# Generated by FakeRAM 2.0
VERSION 5.7 ;
BUSBITCHARS "[]" ;
PROPERTYDEFINITIONS
  MACRO width INTEGER ;
  MACRO depth INTEGER ;
  MACRO banks INTEGER ;
END PROPERTYDEFINITIONS
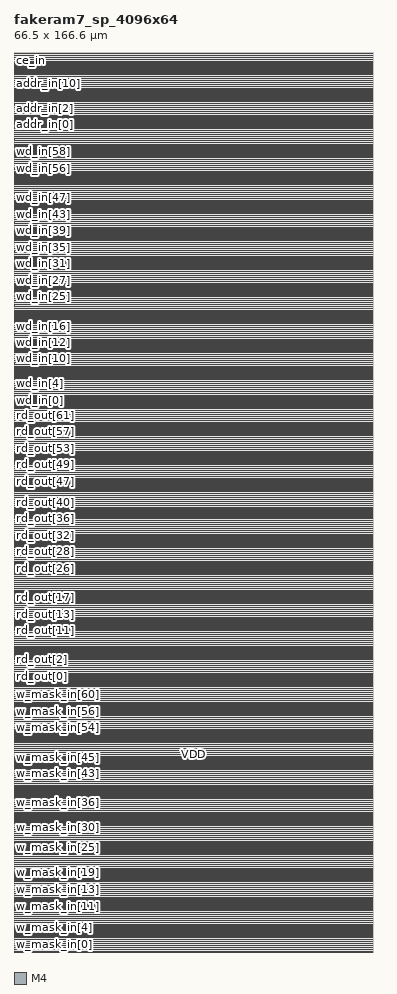
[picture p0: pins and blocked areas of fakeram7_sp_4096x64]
MACRO fakeram7_sp_4096x64
  PROPERTY width 64 ;
  PROPERTY depth 4096 ;
  PROPERTY banks 8 ;
  FOREIGN fakeram7_sp_4096x64 0 0 ;
  SYMMETRY X Y ;
  SIZE 66.500 BY 166.600 ;
  CLASS BLOCK ;
  PIN w_mask_in[0]
    DIRECTION INPUT ;
    USE SIGNAL ;
    SHAPE ABUTMENT ;
    PORT
      LAYER M4 ;
      RECT 0.000 0.048 0.024 0.072 ;
    END
  END w_mask_in[0]
  PIN w_mask_in[1]
    DIRECTION INPUT ;
    USE SIGNAL ;
    SHAPE ABUTMENT ;
    PORT
      LAYER M4 ;
      RECT 0.000 0.816 0.024 0.840 ;
    END
  END w_mask_in[1]
  PIN w_mask_in[2]
    DIRECTION INPUT ;
    USE SIGNAL ;
    SHAPE ABUTMENT ;
    PORT
      LAYER M4 ;
      RECT 0.000 1.584 0.024 1.608 ;
    END
  END w_mask_in[2]
  PIN w_mask_in[3]
    DIRECTION INPUT ;
    USE SIGNAL ;
    SHAPE ABUTMENT ;
    PORT
      LAYER M4 ;
      RECT 0.000 2.352 0.024 2.376 ;
    END
  END w_mask_in[3]
  PIN w_mask_in[4]
    DIRECTION INPUT ;
    USE SIGNAL ;
    SHAPE ABUTMENT ;
    PORT
      LAYER M4 ;
      RECT 0.000 3.120 0.024 3.144 ;
    END
  END w_mask_in[4]
  PIN w_mask_in[5]
    DIRECTION INPUT ;
    USE SIGNAL ;
    SHAPE ABUTMENT ;
    PORT
      LAYER M4 ;
      RECT 0.000 3.888 0.024 3.912 ;
    END
  END w_mask_in[5]
  PIN w_mask_in[6]
    DIRECTION INPUT ;
    USE SIGNAL ;
    SHAPE ABUTMENT ;
    PORT
      LAYER M4 ;
      RECT 0.000 4.656 0.024 4.680 ;
    END
  END w_mask_in[6]
  PIN w_mask_in[7]
    DIRECTION INPUT ;
    USE SIGNAL ;
    SHAPE ABUTMENT ;
    PORT
      LAYER M4 ;
      RECT 0.000 5.424 0.024 5.448 ;
    END
  END w_mask_in[7]
  PIN w_mask_in[8]
    DIRECTION INPUT ;
    USE SIGNAL ;
    SHAPE ABUTMENT ;
    PORT
      LAYER M4 ;
      RECT 0.000 6.192 0.024 6.216 ;
    END
  END w_mask_in[8]
  PIN w_mask_in[9]
    DIRECTION INPUT ;
    USE SIGNAL ;
    SHAPE ABUTMENT ;
    PORT
      LAYER M4 ;
      RECT 0.000 6.960 0.024 6.984 ;
    END
  END w_mask_in[9]
  PIN w_mask_in[10]
    DIRECTION INPUT ;
    USE SIGNAL ;
    SHAPE ABUTMENT ;
    PORT
      LAYER M4 ;
      RECT 0.000 7.728 0.024 7.752 ;
    END
  END w_mask_in[10]
  PIN w_mask_in[11]
    DIRECTION INPUT ;
    USE SIGNAL ;
    SHAPE ABUTMENT ;
    PORT
      LAYER M4 ;
      RECT 0.000 8.496 0.024 8.520 ;
    END
  END w_mask_in[11]
  PIN w_mask_in[12]
    DIRECTION INPUT ;
    USE SIGNAL ;
    SHAPE ABUTMENT ;
    PORT
      LAYER M4 ;
      RECT 0.000 9.264 0.024 9.288 ;
    END
  END w_mask_in[12]
  PIN w_mask_in[13]
    DIRECTION INPUT ;
    USE SIGNAL ;
    SHAPE ABUTMENT ;
    PORT
      LAYER M4 ;
      RECT 0.000 10.032 0.024 10.056 ;
    END
  END w_mask_in[13]
  PIN w_mask_in[14]
    DIRECTION INPUT ;
    USE SIGNAL ;
    SHAPE ABUTMENT ;
    PORT
      LAYER M4 ;
      RECT 0.000 10.800 0.024 10.824 ;
    END
  END w_mask_in[14]
  PIN w_mask_in[15]
    DIRECTION INPUT ;
    USE SIGNAL ;
    SHAPE ABUTMENT ;
    PORT
      LAYER M4 ;
      RECT 0.000 11.568 0.024 11.592 ;
    END
  END w_mask_in[15]
  PIN w_mask_in[16]
    DIRECTION INPUT ;
    USE SIGNAL ;
    SHAPE ABUTMENT ;
    PORT
      LAYER M4 ;
      RECT 0.000 12.336 0.024 12.360 ;
    END
  END w_mask_in[16]
  PIN w_mask_in[17]
    DIRECTION INPUT ;
    USE SIGNAL ;
    SHAPE ABUTMENT ;
    PORT
      LAYER M4 ;
      RECT 0.000 13.104 0.024 13.128 ;
    END
  END w_mask_in[17]
  PIN w_mask_in[18]
    DIRECTION INPUT ;
    USE SIGNAL ;
    SHAPE ABUTMENT ;
    PORT
      LAYER M4 ;
      RECT 0.000 13.872 0.024 13.896 ;
    END
  END w_mask_in[18]
  PIN w_mask_in[19]
    DIRECTION INPUT ;
    USE SIGNAL ;
    SHAPE ABUTMENT ;
    PORT
      LAYER M4 ;
      RECT 0.000 14.640 0.024 14.664 ;
    END
  END w_mask_in[19]
  PIN w_mask_in[20]
    DIRECTION INPUT ;
    USE SIGNAL ;
    SHAPE ABUTMENT ;
    PORT
      LAYER M4 ;
      RECT 0.000 15.408 0.024 15.432 ;
    END
  END w_mask_in[20]
  PIN w_mask_in[21]
    DIRECTION INPUT ;
    USE SIGNAL ;
    SHAPE ABUTMENT ;
    PORT
      LAYER M4 ;
      RECT 0.000 16.176 0.024 16.200 ;
    END
  END w_mask_in[21]
  PIN w_mask_in[22]
    DIRECTION INPUT ;
    USE SIGNAL ;
    SHAPE ABUTMENT ;
    PORT
      LAYER M4 ;
      RECT 0.000 16.944 0.024 16.968 ;
    END
  END w_mask_in[22]
  PIN w_mask_in[23]
    DIRECTION INPUT ;
    USE SIGNAL ;
    SHAPE ABUTMENT ;
    PORT
      LAYER M4 ;
      RECT 0.000 17.712 0.024 17.736 ;
    END
  END w_mask_in[23]
  PIN w_mask_in[24]
    DIRECTION INPUT ;
    USE SIGNAL ;
    SHAPE ABUTMENT ;
    PORT
      LAYER M4 ;
      RECT 0.000 18.480 0.024 18.504 ;
    END
  END w_mask_in[24]
  PIN w_mask_in[25]
    DIRECTION INPUT ;
    USE SIGNAL ;
    SHAPE ABUTMENT ;
    PORT
      LAYER M4 ;
      RECT 0.000 19.248 0.024 19.272 ;
    END
  END w_mask_in[25]
  PIN w_mask_in[26]
    DIRECTION INPUT ;
    USE SIGNAL ;
    SHAPE ABUTMENT ;
    PORT
      LAYER M4 ;
      RECT 0.000 20.016 0.024 20.040 ;
    END
  END w_mask_in[26]
  PIN w_mask_in[27]
    DIRECTION INPUT ;
    USE SIGNAL ;
    SHAPE ABUTMENT ;
    PORT
      LAYER M4 ;
      RECT 0.000 20.784 0.024 20.808 ;
    END
  END w_mask_in[27]
  PIN w_mask_in[28]
    DIRECTION INPUT ;
    USE SIGNAL ;
    SHAPE ABUTMENT ;
    PORT
      LAYER M4 ;
      RECT 0.000 21.552 0.024 21.576 ;
    END
  END w_mask_in[28]
  PIN w_mask_in[29]
    DIRECTION INPUT ;
    USE SIGNAL ;
    SHAPE ABUTMENT ;
    PORT
      LAYER M4 ;
      RECT 0.000 22.320 0.024 22.344 ;
    END
  END w_mask_in[29]
  PIN w_mask_in[30]
    DIRECTION INPUT ;
    USE SIGNAL ;
    SHAPE ABUTMENT ;
    PORT
      LAYER M4 ;
      RECT 0.000 23.088 0.024 23.112 ;
    END
  END w_mask_in[30]
  PIN w_mask_in[31]
    DIRECTION INPUT ;
    USE SIGNAL ;
    SHAPE ABUTMENT ;
    PORT
      LAYER M4 ;
      RECT 0.000 23.856 0.024 23.880 ;
    END
  END w_mask_in[31]
  PIN w_mask_in[32]
    DIRECTION INPUT ;
    USE SIGNAL ;
    SHAPE ABUTMENT ;
    PORT
      LAYER M4 ;
      RECT 0.000 24.624 0.024 24.648 ;
    END
  END w_mask_in[32]
  PIN w_mask_in[33]
    DIRECTION INPUT ;
    USE SIGNAL ;
    SHAPE ABUTMENT ;
    PORT
      LAYER M4 ;
      RECT 0.000 25.392 0.024 25.416 ;
    END
  END w_mask_in[33]
  PIN w_mask_in[34]
    DIRECTION INPUT ;
    USE SIGNAL ;
    SHAPE ABUTMENT ;
    PORT
      LAYER M4 ;
      RECT 0.000 26.160 0.024 26.184 ;
    END
  END w_mask_in[34]
  PIN w_mask_in[35]
    DIRECTION INPUT ;
    USE SIGNAL ;
    SHAPE ABUTMENT ;
    PORT
      LAYER M4 ;
      RECT 0.000 26.928 0.024 26.952 ;
    END
  END w_mask_in[35]
  PIN w_mask_in[36]
    DIRECTION INPUT ;
    USE SIGNAL ;
    SHAPE ABUTMENT ;
    PORT
      LAYER M4 ;
      RECT 0.000 27.696 0.024 27.720 ;
    END
  END w_mask_in[36]
  PIN w_mask_in[37]
    DIRECTION INPUT ;
    USE SIGNAL ;
    SHAPE ABUTMENT ;
    PORT
      LAYER M4 ;
      RECT 0.000 28.464 0.024 28.488 ;
    END
  END w_mask_in[37]
  PIN w_mask_in[38]
    DIRECTION INPUT ;
    USE SIGNAL ;
    SHAPE ABUTMENT ;
    PORT
      LAYER M4 ;
      RECT 0.000 29.232 0.024 29.256 ;
    END
  END w_mask_in[38]
  PIN w_mask_in[39]
    DIRECTION INPUT ;
    USE SIGNAL ;
    SHAPE ABUTMENT ;
    PORT
      LAYER M4 ;
      RECT 0.000 30.000 0.024 30.024 ;
    END
  END w_mask_in[39]
  PIN w_mask_in[40]
    DIRECTION INPUT ;
    USE SIGNAL ;
    SHAPE ABUTMENT ;
    PORT
      LAYER M4 ;
      RECT 0.000 30.768 0.024 30.792 ;
    END
  END w_mask_in[40]
  PIN w_mask_in[41]
    DIRECTION INPUT ;
    USE SIGNAL ;
    SHAPE ABUTMENT ;
    PORT
      LAYER M4 ;
      RECT 0.000 31.536 0.024 31.560 ;
    END
  END w_mask_in[41]
  PIN w_mask_in[42]
    DIRECTION INPUT ;
    USE SIGNAL ;
    SHAPE ABUTMENT ;
    PORT
      LAYER M4 ;
      RECT 0.000 32.304 0.024 32.328 ;
    END
  END w_mask_in[42]
  PIN w_mask_in[43]
    DIRECTION INPUT ;
    USE SIGNAL ;
    SHAPE ABUTMENT ;
    PORT
      LAYER M4 ;
      RECT 0.000 33.072 0.024 33.096 ;
    END
  END w_mask_in[43]
  PIN w_mask_in[44]
    DIRECTION INPUT ;
    USE SIGNAL ;
    SHAPE ABUTMENT ;
    PORT
      LAYER M4 ;
      RECT 0.000 33.840 0.024 33.864 ;
    END
  END w_mask_in[44]
  PIN w_mask_in[45]
    DIRECTION INPUT ;
    USE SIGNAL ;
    SHAPE ABUTMENT ;
    PORT
      LAYER M4 ;
      RECT 0.000 34.608 0.024 34.632 ;
    END
  END w_mask_in[45]
  PIN w_mask_in[46]
    DIRECTION INPUT ;
    USE SIGNAL ;
    SHAPE ABUTMENT ;
    PORT
      LAYER M4 ;
      RECT 0.000 35.376 0.024 35.400 ;
    END
  END w_mask_in[46]
  PIN w_mask_in[47]
    DIRECTION INPUT ;
    USE SIGNAL ;
    SHAPE ABUTMENT ;
    PORT
      LAYER M4 ;
      RECT 0.000 36.144 0.024 36.168 ;
    END
  END w_mask_in[47]
  PIN w_mask_in[48]
    DIRECTION INPUT ;
    USE SIGNAL ;
    SHAPE ABUTMENT ;
    PORT
      LAYER M4 ;
      RECT 0.000 36.912 0.024 36.936 ;
    END
  END w_mask_in[48]
  PIN w_mask_in[49]
    DIRECTION INPUT ;
    USE SIGNAL ;
    SHAPE ABUTMENT ;
    PORT
      LAYER M4 ;
      RECT 0.000 37.680 0.024 37.704 ;
    END
  END w_mask_in[49]
  PIN w_mask_in[50]
    DIRECTION INPUT ;
    USE SIGNAL ;
    SHAPE ABUTMENT ;
    PORT
      LAYER M4 ;
      RECT 0.000 38.448 0.024 38.472 ;
    END
  END w_mask_in[50]
  PIN w_mask_in[51]
    DIRECTION INPUT ;
    USE SIGNAL ;
    SHAPE ABUTMENT ;
    PORT
      LAYER M4 ;
      RECT 0.000 39.216 0.024 39.240 ;
    END
  END w_mask_in[51]
  PIN w_mask_in[52]
    DIRECTION INPUT ;
    USE SIGNAL ;
    SHAPE ABUTMENT ;
    PORT
      LAYER M4 ;
      RECT 0.000 39.984 0.024 40.008 ;
    END
  END w_mask_in[52]
  PIN w_mask_in[53]
    DIRECTION INPUT ;
    USE SIGNAL ;
    SHAPE ABUTMENT ;
    PORT
      LAYER M4 ;
      RECT 0.000 40.752 0.024 40.776 ;
    END
  END w_mask_in[53]
  PIN w_mask_in[54]
    DIRECTION INPUT ;
    USE SIGNAL ;
    SHAPE ABUTMENT ;
    PORT
      LAYER M4 ;
      RECT 0.000 41.520 0.024 41.544 ;
    END
  END w_mask_in[54]
  PIN w_mask_in[55]
    DIRECTION INPUT ;
    USE SIGNAL ;
    SHAPE ABUTMENT ;
    PORT
      LAYER M4 ;
      RECT 0.000 42.288 0.024 42.312 ;
    END
  END w_mask_in[55]
  PIN w_mask_in[56]
    DIRECTION INPUT ;
    USE SIGNAL ;
    SHAPE ABUTMENT ;
    PORT
      LAYER M4 ;
      RECT 0.000 43.056 0.024 43.080 ;
    END
  END w_mask_in[56]
  PIN w_mask_in[57]
    DIRECTION INPUT ;
    USE SIGNAL ;
    SHAPE ABUTMENT ;
    PORT
      LAYER M4 ;
      RECT 0.000 43.824 0.024 43.848 ;
    END
  END w_mask_in[57]
  PIN w_mask_in[58]
    DIRECTION INPUT ;
    USE SIGNAL ;
    SHAPE ABUTMENT ;
    PORT
      LAYER M4 ;
      RECT 0.000 44.592 0.024 44.616 ;
    END
  END w_mask_in[58]
  PIN w_mask_in[59]
    DIRECTION INPUT ;
    USE SIGNAL ;
    SHAPE ABUTMENT ;
    PORT
      LAYER M4 ;
      RECT 0.000 45.360 0.024 45.384 ;
    END
  END w_mask_in[59]
  PIN w_mask_in[60]
    DIRECTION INPUT ;
    USE SIGNAL ;
    SHAPE ABUTMENT ;
    PORT
      LAYER M4 ;
      RECT 0.000 46.128 0.024 46.152 ;
    END
  END w_mask_in[60]
  PIN w_mask_in[61]
    DIRECTION INPUT ;
    USE SIGNAL ;
    SHAPE ABUTMENT ;
    PORT
      LAYER M4 ;
      RECT 0.000 46.896 0.024 46.920 ;
    END
  END w_mask_in[61]
  PIN w_mask_in[62]
    DIRECTION INPUT ;
    USE SIGNAL ;
    SHAPE ABUTMENT ;
    PORT
      LAYER M4 ;
      RECT 0.000 47.664 0.024 47.688 ;
    END
  END w_mask_in[62]
  PIN w_mask_in[63]
    DIRECTION INPUT ;
    USE SIGNAL ;
    SHAPE ABUTMENT ;
    PORT
      LAYER M4 ;
      RECT 0.000 48.432 0.024 48.456 ;
    END
  END w_mask_in[63]
  PIN rd_out[0]
    DIRECTION OUTPUT ;
    USE SIGNAL ;
    SHAPE ABUTMENT ;
    PORT
      LAYER M4 ;
      RECT 0.000 51.072 0.024 51.096 ;
    END
  END rd_out[0]
  PIN rd_out[1]
    DIRECTION OUTPUT ;
    USE SIGNAL ;
    SHAPE ABUTMENT ;
    PORT
      LAYER M4 ;
      RECT 0.000 51.840 0.024 51.864 ;
    END
  END rd_out[1]
  PIN rd_out[2]
    DIRECTION OUTPUT ;
    USE SIGNAL ;
    SHAPE ABUTMENT ;
    PORT
      LAYER M4 ;
      RECT 0.000 52.608 0.024 52.632 ;
    END
  END rd_out[2]
  PIN rd_out[3]
    DIRECTION OUTPUT ;
    USE SIGNAL ;
    SHAPE ABUTMENT ;
    PORT
      LAYER M4 ;
      RECT 0.000 53.376 0.024 53.400 ;
    END
  END rd_out[3]
  PIN rd_out[4]
    DIRECTION OUTPUT ;
    USE SIGNAL ;
    SHAPE ABUTMENT ;
    PORT
      LAYER M4 ;
      RECT 0.000 54.144 0.024 54.168 ;
    END
  END rd_out[4]
  PIN rd_out[5]
    DIRECTION OUTPUT ;
    USE SIGNAL ;
    SHAPE ABUTMENT ;
    PORT
      LAYER M4 ;
      RECT 0.000 54.912 0.024 54.936 ;
    END
  END rd_out[5]
  PIN rd_out[6]
    DIRECTION OUTPUT ;
    USE SIGNAL ;
    SHAPE ABUTMENT ;
    PORT
      LAYER M4 ;
      RECT 0.000 55.680 0.024 55.704 ;
    END
  END rd_out[6]
  PIN rd_out[7]
    DIRECTION OUTPUT ;
    USE SIGNAL ;
    SHAPE ABUTMENT ;
    PORT
      LAYER M4 ;
      RECT 0.000 56.448 0.024 56.472 ;
    END
  END rd_out[7]
  PIN rd_out[8]
    DIRECTION OUTPUT ;
    USE SIGNAL ;
    SHAPE ABUTMENT ;
    PORT
      LAYER M4 ;
      RECT 0.000 57.216 0.024 57.240 ;
    END
  END rd_out[8]
  PIN rd_out[9]
    DIRECTION OUTPUT ;
    USE SIGNAL ;
    SHAPE ABUTMENT ;
    PORT
      LAYER M4 ;
      RECT 0.000 57.984 0.024 58.008 ;
    END
  END rd_out[9]
  PIN rd_out[10]
    DIRECTION OUTPUT ;
    USE SIGNAL ;
    SHAPE ABUTMENT ;
    PORT
      LAYER M4 ;
      RECT 0.000 58.752 0.024 58.776 ;
    END
  END rd_out[10]
  PIN rd_out[11]
    DIRECTION OUTPUT ;
    USE SIGNAL ;
    SHAPE ABUTMENT ;
    PORT
      LAYER M4 ;
      RECT 0.000 59.520 0.024 59.544 ;
    END
  END rd_out[11]
  PIN rd_out[12]
    DIRECTION OUTPUT ;
    USE SIGNAL ;
    SHAPE ABUTMENT ;
    PORT
      LAYER M4 ;
      RECT 0.000 60.288 0.024 60.312 ;
    END
  END rd_out[12]
  PIN rd_out[13]
    DIRECTION OUTPUT ;
    USE SIGNAL ;
    SHAPE ABUTMENT ;
    PORT
      LAYER M4 ;
      RECT 0.000 61.056 0.024 61.080 ;
    END
  END rd_out[13]
  PIN rd_out[14]
    DIRECTION OUTPUT ;
    USE SIGNAL ;
    SHAPE ABUTMENT ;
    PORT
      LAYER M4 ;
      RECT 0.000 61.824 0.024 61.848 ;
    END
  END rd_out[14]
  PIN rd_out[15]
    DIRECTION OUTPUT ;
    USE SIGNAL ;
    SHAPE ABUTMENT ;
    PORT
      LAYER M4 ;
      RECT 0.000 62.592 0.024 62.616 ;
    END
  END rd_out[15]
  PIN rd_out[16]
    DIRECTION OUTPUT ;
    USE SIGNAL ;
    SHAPE ABUTMENT ;
    PORT
      LAYER M4 ;
      RECT 0.000 63.360 0.024 63.384 ;
    END
  END rd_out[16]
  PIN rd_out[17]
    DIRECTION OUTPUT ;
    USE SIGNAL ;
    SHAPE ABUTMENT ;
    PORT
      LAYER M4 ;
      RECT 0.000 64.128 0.024 64.152 ;
    END
  END rd_out[17]
  PIN rd_out[18]
    DIRECTION OUTPUT ;
    USE SIGNAL ;
    SHAPE ABUTMENT ;
    PORT
      LAYER M4 ;
      RECT 0.000 64.896 0.024 64.920 ;
    END
  END rd_out[18]
  PIN rd_out[19]
    DIRECTION OUTPUT ;
    USE SIGNAL ;
    SHAPE ABUTMENT ;
    PORT
      LAYER M4 ;
      RECT 0.000 65.664 0.024 65.688 ;
    END
  END rd_out[19]
  PIN rd_out[20]
    DIRECTION OUTPUT ;
    USE SIGNAL ;
    SHAPE ABUTMENT ;
    PORT
      LAYER M4 ;
      RECT 0.000 66.432 0.024 66.456 ;
    END
  END rd_out[20]
  PIN rd_out[21]
    DIRECTION OUTPUT ;
    USE SIGNAL ;
    SHAPE ABUTMENT ;
    PORT
      LAYER M4 ;
      RECT 0.000 67.200 0.024 67.224 ;
    END
  END rd_out[21]
  PIN rd_out[22]
    DIRECTION OUTPUT ;
    USE SIGNAL ;
    SHAPE ABUTMENT ;
    PORT
      LAYER M4 ;
      RECT 0.000 67.968 0.024 67.992 ;
    END
  END rd_out[22]
  PIN rd_out[23]
    DIRECTION OUTPUT ;
    USE SIGNAL ;
    SHAPE ABUTMENT ;
    PORT
      LAYER M4 ;
      RECT 0.000 68.736 0.024 68.760 ;
    END
  END rd_out[23]
  PIN rd_out[24]
    DIRECTION OUTPUT ;
    USE SIGNAL ;
    SHAPE ABUTMENT ;
    PORT
      LAYER M4 ;
      RECT 0.000 69.504 0.024 69.528 ;
    END
  END rd_out[24]
  PIN rd_out[25]
    DIRECTION OUTPUT ;
    USE SIGNAL ;
    SHAPE ABUTMENT ;
    PORT
      LAYER M4 ;
      RECT 0.000 70.272 0.024 70.296 ;
    END
  END rd_out[25]
  PIN rd_out[26]
    DIRECTION OUTPUT ;
    USE SIGNAL ;
    SHAPE ABUTMENT ;
    PORT
      LAYER M4 ;
      RECT 0.000 71.040 0.024 71.064 ;
    END
  END rd_out[26]
  PIN rd_out[27]
    DIRECTION OUTPUT ;
    USE SIGNAL ;
    SHAPE ABUTMENT ;
    PORT
      LAYER M4 ;
      RECT 0.000 71.808 0.024 71.832 ;
    END
  END rd_out[27]
  PIN rd_out[28]
    DIRECTION OUTPUT ;
    USE SIGNAL ;
    SHAPE ABUTMENT ;
    PORT
      LAYER M4 ;
      RECT 0.000 72.576 0.024 72.600 ;
    END
  END rd_out[28]
  PIN rd_out[29]
    DIRECTION OUTPUT ;
    USE SIGNAL ;
    SHAPE ABUTMENT ;
    PORT
      LAYER M4 ;
      RECT 0.000 73.344 0.024 73.368 ;
    END
  END rd_out[29]
  PIN rd_out[30]
    DIRECTION OUTPUT ;
    USE SIGNAL ;
    SHAPE ABUTMENT ;
    PORT
      LAYER M4 ;
      RECT 0.000 74.112 0.024 74.136 ;
    END
  END rd_out[30]
  PIN rd_out[31]
    DIRECTION OUTPUT ;
    USE SIGNAL ;
    SHAPE ABUTMENT ;
    PORT
      LAYER M4 ;
      RECT 0.000 74.880 0.024 74.904 ;
    END
  END rd_out[31]
  PIN rd_out[32]
    DIRECTION OUTPUT ;
    USE SIGNAL ;
    SHAPE ABUTMENT ;
    PORT
      LAYER M4 ;
      RECT 0.000 75.648 0.024 75.672 ;
    END
  END rd_out[32]
  PIN rd_out[33]
    DIRECTION OUTPUT ;
    USE SIGNAL ;
    SHAPE ABUTMENT ;
    PORT
      LAYER M4 ;
      RECT 0.000 76.416 0.024 76.440 ;
    END
  END rd_out[33]
  PIN rd_out[34]
    DIRECTION OUTPUT ;
    USE SIGNAL ;
    SHAPE ABUTMENT ;
    PORT
      LAYER M4 ;
      RECT 0.000 77.184 0.024 77.208 ;
    END
  END rd_out[34]
  PIN rd_out[35]
    DIRECTION OUTPUT ;
    USE SIGNAL ;
    SHAPE ABUTMENT ;
    PORT
      LAYER M4 ;
      RECT 0.000 77.952 0.024 77.976 ;
    END
  END rd_out[35]
  PIN rd_out[36]
    DIRECTION OUTPUT ;
    USE SIGNAL ;
    SHAPE ABUTMENT ;
    PORT
      LAYER M4 ;
      RECT 0.000 78.720 0.024 78.744 ;
    END
  END rd_out[36]
  PIN rd_out[37]
    DIRECTION OUTPUT ;
    USE SIGNAL ;
    SHAPE ABUTMENT ;
    PORT
      LAYER M4 ;
      RECT 0.000 79.488 0.024 79.512 ;
    END
  END rd_out[37]
  PIN rd_out[38]
    DIRECTION OUTPUT ;
    USE SIGNAL ;
    SHAPE ABUTMENT ;
    PORT
      LAYER M4 ;
      RECT 0.000 80.256 0.024 80.280 ;
    END
  END rd_out[38]
  PIN rd_out[39]
    DIRECTION OUTPUT ;
    USE SIGNAL ;
    SHAPE ABUTMENT ;
    PORT
      LAYER M4 ;
      RECT 0.000 81.024 0.024 81.048 ;
    END
  END rd_out[39]
  PIN rd_out[40]
    DIRECTION OUTPUT ;
    USE SIGNAL ;
    SHAPE ABUTMENT ;
    PORT
      LAYER M4 ;
      RECT 0.000 81.792 0.024 81.816 ;
    END
  END rd_out[40]
  PIN rd_out[41]
    DIRECTION OUTPUT ;
    USE SIGNAL ;
    SHAPE ABUTMENT ;
    PORT
      LAYER M4 ;
      RECT 0.000 82.560 0.024 82.584 ;
    END
  END rd_out[41]
  PIN rd_out[42]
    DIRECTION OUTPUT ;
    USE SIGNAL ;
    SHAPE ABUTMENT ;
    PORT
      LAYER M4 ;
      RECT 0.000 83.328 0.024 83.352 ;
    END
  END rd_out[42]
  PIN rd_out[43]
    DIRECTION OUTPUT ;
    USE SIGNAL ;
    SHAPE ABUTMENT ;
    PORT
      LAYER M4 ;
      RECT 0.000 84.096 0.024 84.120 ;
    END
  END rd_out[43]
  PIN rd_out[44]
    DIRECTION OUTPUT ;
    USE SIGNAL ;
    SHAPE ABUTMENT ;
    PORT
      LAYER M4 ;
      RECT 0.000 84.864 0.024 84.888 ;
    END
  END rd_out[44]
  PIN rd_out[45]
    DIRECTION OUTPUT ;
    USE SIGNAL ;
    SHAPE ABUTMENT ;
    PORT
      LAYER M4 ;
      RECT 0.000 85.632 0.024 85.656 ;
    END
  END rd_out[45]
  PIN rd_out[46]
    DIRECTION OUTPUT ;
    USE SIGNAL ;
    SHAPE ABUTMENT ;
    PORT
      LAYER M4 ;
      RECT 0.000 86.400 0.024 86.424 ;
    END
  END rd_out[46]
  PIN rd_out[47]
    DIRECTION OUTPUT ;
    USE SIGNAL ;
    SHAPE ABUTMENT ;
    PORT
      LAYER M4 ;
      RECT 0.000 87.168 0.024 87.192 ;
    END
  END rd_out[47]
  PIN rd_out[48]
    DIRECTION OUTPUT ;
    USE SIGNAL ;
    SHAPE ABUTMENT ;
    PORT
      LAYER M4 ;
      RECT 0.000 87.936 0.024 87.960 ;
    END
  END rd_out[48]
  PIN rd_out[49]
    DIRECTION OUTPUT ;
    USE SIGNAL ;
    SHAPE ABUTMENT ;
    PORT
      LAYER M4 ;
      RECT 0.000 88.704 0.024 88.728 ;
    END
  END rd_out[49]
  PIN rd_out[50]
    DIRECTION OUTPUT ;
    USE SIGNAL ;
    SHAPE ABUTMENT ;
    PORT
      LAYER M4 ;
      RECT 0.000 89.472 0.024 89.496 ;
    END
  END rd_out[50]
  PIN rd_out[51]
    DIRECTION OUTPUT ;
    USE SIGNAL ;
    SHAPE ABUTMENT ;
    PORT
      LAYER M4 ;
      RECT 0.000 90.240 0.024 90.264 ;
    END
  END rd_out[51]
  PIN rd_out[52]
    DIRECTION OUTPUT ;
    USE SIGNAL ;
    SHAPE ABUTMENT ;
    PORT
      LAYER M4 ;
      RECT 0.000 91.008 0.024 91.032 ;
    END
  END rd_out[52]
  PIN rd_out[53]
    DIRECTION OUTPUT ;
    USE SIGNAL ;
    SHAPE ABUTMENT ;
    PORT
      LAYER M4 ;
      RECT 0.000 91.776 0.024 91.800 ;
    END
  END rd_out[53]
  PIN rd_out[54]
    DIRECTION OUTPUT ;
    USE SIGNAL ;
    SHAPE ABUTMENT ;
    PORT
      LAYER M4 ;
      RECT 0.000 92.544 0.024 92.568 ;
    END
  END rd_out[54]
  PIN rd_out[55]
    DIRECTION OUTPUT ;
    USE SIGNAL ;
    SHAPE ABUTMENT ;
    PORT
      LAYER M4 ;
      RECT 0.000 93.312 0.024 93.336 ;
    END
  END rd_out[55]
  PIN rd_out[56]
    DIRECTION OUTPUT ;
    USE SIGNAL ;
    SHAPE ABUTMENT ;
    PORT
      LAYER M4 ;
      RECT 0.000 94.080 0.024 94.104 ;
    END
  END rd_out[56]
  PIN rd_out[57]
    DIRECTION OUTPUT ;
    USE SIGNAL ;
    SHAPE ABUTMENT ;
    PORT
      LAYER M4 ;
      RECT 0.000 94.848 0.024 94.872 ;
    END
  END rd_out[57]
  PIN rd_out[58]
    DIRECTION OUTPUT ;
    USE SIGNAL ;
    SHAPE ABUTMENT ;
    PORT
      LAYER M4 ;
      RECT 0.000 95.616 0.024 95.640 ;
    END
  END rd_out[58]
  PIN rd_out[59]
    DIRECTION OUTPUT ;
    USE SIGNAL ;
    SHAPE ABUTMENT ;
    PORT
      LAYER M4 ;
      RECT 0.000 96.384 0.024 96.408 ;
    END
  END rd_out[59]
  PIN rd_out[60]
    DIRECTION OUTPUT ;
    USE SIGNAL ;
    SHAPE ABUTMENT ;
    PORT
      LAYER M4 ;
      RECT 0.000 97.152 0.024 97.176 ;
    END
  END rd_out[60]
  PIN rd_out[61]
    DIRECTION OUTPUT ;
    USE SIGNAL ;
    SHAPE ABUTMENT ;
    PORT
      LAYER M4 ;
      RECT 0.000 97.920 0.024 97.944 ;
    END
  END rd_out[61]
  PIN rd_out[62]
    DIRECTION OUTPUT ;
    USE SIGNAL ;
    SHAPE ABUTMENT ;
    PORT
      LAYER M4 ;
      RECT 0.000 98.688 0.024 98.712 ;
    END
  END rd_out[62]
  PIN rd_out[63]
    DIRECTION OUTPUT ;
    USE SIGNAL ;
    SHAPE ABUTMENT ;
    PORT
      LAYER M4 ;
      RECT 0.000 99.456 0.024 99.480 ;
    END
  END rd_out[63]
  PIN wd_in[0]
    DIRECTION INPUT ;
    USE SIGNAL ;
    SHAPE ABUTMENT ;
    PORT
      LAYER M4 ;
      RECT 0.000 102.096 0.024 102.120 ;
    END
  END wd_in[0]
  PIN wd_in[1]
    DIRECTION INPUT ;
    USE SIGNAL ;
    SHAPE ABUTMENT ;
    PORT
      LAYER M4 ;
      RECT 0.000 102.864 0.024 102.888 ;
    END
  END wd_in[1]
  PIN wd_in[2]
    DIRECTION INPUT ;
    USE SIGNAL ;
    SHAPE ABUTMENT ;
    PORT
      LAYER M4 ;
      RECT 0.000 103.632 0.024 103.656 ;
    END
  END wd_in[2]
  PIN wd_in[3]
    DIRECTION INPUT ;
    USE SIGNAL ;
    SHAPE ABUTMENT ;
    PORT
      LAYER M4 ;
      RECT 0.000 104.400 0.024 104.424 ;
    END
  END wd_in[3]
  PIN wd_in[4]
    DIRECTION INPUT ;
    USE SIGNAL ;
    SHAPE ABUTMENT ;
    PORT
      LAYER M4 ;
      RECT 0.000 105.168 0.024 105.192 ;
    END
  END wd_in[4]
  PIN wd_in[5]
    DIRECTION INPUT ;
    USE SIGNAL ;
    SHAPE ABUTMENT ;
    PORT
      LAYER M4 ;
      RECT 0.000 105.936 0.024 105.960 ;
    END
  END wd_in[5]
  PIN wd_in[6]
    DIRECTION INPUT ;
    USE SIGNAL ;
    SHAPE ABUTMENT ;
    PORT
      LAYER M4 ;
      RECT 0.000 106.704 0.024 106.728 ;
    END
  END wd_in[6]
  PIN wd_in[7]
    DIRECTION INPUT ;
    USE SIGNAL ;
    SHAPE ABUTMENT ;
    PORT
      LAYER M4 ;
      RECT 0.000 107.472 0.024 107.496 ;
    END
  END wd_in[7]
  PIN wd_in[8]
    DIRECTION INPUT ;
    USE SIGNAL ;
    SHAPE ABUTMENT ;
    PORT
      LAYER M4 ;
      RECT 0.000 108.240 0.024 108.264 ;
    END
  END wd_in[8]
  PIN wd_in[9]
    DIRECTION INPUT ;
    USE SIGNAL ;
    SHAPE ABUTMENT ;
    PORT
      LAYER M4 ;
      RECT 0.000 109.008 0.024 109.032 ;
    END
  END wd_in[9]
  PIN wd_in[10]
    DIRECTION INPUT ;
    USE SIGNAL ;
    SHAPE ABUTMENT ;
    PORT
      LAYER M4 ;
      RECT 0.000 109.776 0.024 109.800 ;
    END
  END wd_in[10]
  PIN wd_in[11]
    DIRECTION INPUT ;
    USE SIGNAL ;
    SHAPE ABUTMENT ;
    PORT
      LAYER M4 ;
      RECT 0.000 110.544 0.024 110.568 ;
    END
  END wd_in[11]
  PIN wd_in[12]
    DIRECTION INPUT ;
    USE SIGNAL ;
    SHAPE ABUTMENT ;
    PORT
      LAYER M4 ;
      RECT 0.000 111.312 0.024 111.336 ;
    END
  END wd_in[12]
  PIN wd_in[13]
    DIRECTION INPUT ;
    USE SIGNAL ;
    SHAPE ABUTMENT ;
    PORT
      LAYER M4 ;
      RECT 0.000 112.080 0.024 112.104 ;
    END
  END wd_in[13]
  PIN wd_in[14]
    DIRECTION INPUT ;
    USE SIGNAL ;
    SHAPE ABUTMENT ;
    PORT
      LAYER M4 ;
      RECT 0.000 112.848 0.024 112.872 ;
    END
  END wd_in[14]
  PIN wd_in[15]
    DIRECTION INPUT ;
    USE SIGNAL ;
    SHAPE ABUTMENT ;
    PORT
      LAYER M4 ;
      RECT 0.000 113.616 0.024 113.640 ;
    END
  END wd_in[15]
  PIN wd_in[16]
    DIRECTION INPUT ;
    USE SIGNAL ;
    SHAPE ABUTMENT ;
    PORT
      LAYER M4 ;
      RECT 0.000 114.384 0.024 114.408 ;
    END
  END wd_in[16]
  PIN wd_in[17]
    DIRECTION INPUT ;
    USE SIGNAL ;
    SHAPE ABUTMENT ;
    PORT
      LAYER M4 ;
      RECT 0.000 115.152 0.024 115.176 ;
    END
  END wd_in[17]
  PIN wd_in[18]
    DIRECTION INPUT ;
    USE SIGNAL ;
    SHAPE ABUTMENT ;
    PORT
      LAYER M4 ;
      RECT 0.000 115.920 0.024 115.944 ;
    END
  END wd_in[18]
  PIN wd_in[19]
    DIRECTION INPUT ;
    USE SIGNAL ;
    SHAPE ABUTMENT ;
    PORT
      LAYER M4 ;
      RECT 0.000 116.688 0.024 116.712 ;
    END
  END wd_in[19]
  PIN wd_in[20]
    DIRECTION INPUT ;
    USE SIGNAL ;
    SHAPE ABUTMENT ;
    PORT
      LAYER M4 ;
      RECT 0.000 117.456 0.024 117.480 ;
    END
  END wd_in[20]
  PIN wd_in[21]
    DIRECTION INPUT ;
    USE SIGNAL ;
    SHAPE ABUTMENT ;
    PORT
      LAYER M4 ;
      RECT 0.000 118.224 0.024 118.248 ;
    END
  END wd_in[21]
  PIN wd_in[22]
    DIRECTION INPUT ;
    USE SIGNAL ;
    SHAPE ABUTMENT ;
    PORT
      LAYER M4 ;
      RECT 0.000 118.992 0.024 119.016 ;
    END
  END wd_in[22]
  PIN wd_in[23]
    DIRECTION INPUT ;
    USE SIGNAL ;
    SHAPE ABUTMENT ;
    PORT
      LAYER M4 ;
      RECT 0.000 119.760 0.024 119.784 ;
    END
  END wd_in[23]
  PIN wd_in[24]
    DIRECTION INPUT ;
    USE SIGNAL ;
    SHAPE ABUTMENT ;
    PORT
      LAYER M4 ;
      RECT 0.000 120.528 0.024 120.552 ;
    END
  END wd_in[24]
  PIN wd_in[25]
    DIRECTION INPUT ;
    USE SIGNAL ;
    SHAPE ABUTMENT ;
    PORT
      LAYER M4 ;
      RECT 0.000 121.296 0.024 121.320 ;
    END
  END wd_in[25]
  PIN wd_in[26]
    DIRECTION INPUT ;
    USE SIGNAL ;
    SHAPE ABUTMENT ;
    PORT
      LAYER M4 ;
      RECT 0.000 122.064 0.024 122.088 ;
    END
  END wd_in[26]
  PIN wd_in[27]
    DIRECTION INPUT ;
    USE SIGNAL ;
    SHAPE ABUTMENT ;
    PORT
      LAYER M4 ;
      RECT 0.000 122.832 0.024 122.856 ;
    END
  END wd_in[27]
  PIN wd_in[28]
    DIRECTION INPUT ;
    USE SIGNAL ;
    SHAPE ABUTMENT ;
    PORT
      LAYER M4 ;
      RECT 0.000 123.600 0.024 123.624 ;
    END
  END wd_in[28]
  PIN wd_in[29]
    DIRECTION INPUT ;
    USE SIGNAL ;
    SHAPE ABUTMENT ;
    PORT
      LAYER M4 ;
      RECT 0.000 124.368 0.024 124.392 ;
    END
  END wd_in[29]
  PIN wd_in[30]
    DIRECTION INPUT ;
    USE SIGNAL ;
    SHAPE ABUTMENT ;
    PORT
      LAYER M4 ;
      RECT 0.000 125.136 0.024 125.160 ;
    END
  END wd_in[30]
  PIN wd_in[31]
    DIRECTION INPUT ;
    USE SIGNAL ;
    SHAPE ABUTMENT ;
    PORT
      LAYER M4 ;
      RECT 0.000 125.904 0.024 125.928 ;
    END
  END wd_in[31]
  PIN wd_in[32]
    DIRECTION INPUT ;
    USE SIGNAL ;
    SHAPE ABUTMENT ;
    PORT
      LAYER M4 ;
      RECT 0.000 126.672 0.024 126.696 ;
    END
  END wd_in[32]
  PIN wd_in[33]
    DIRECTION INPUT ;
    USE SIGNAL ;
    SHAPE ABUTMENT ;
    PORT
      LAYER M4 ;
      RECT 0.000 127.440 0.024 127.464 ;
    END
  END wd_in[33]
  PIN wd_in[34]
    DIRECTION INPUT ;
    USE SIGNAL ;
    SHAPE ABUTMENT ;
    PORT
      LAYER M4 ;
      RECT 0.000 128.208 0.024 128.232 ;
    END
  END wd_in[34]
  PIN wd_in[35]
    DIRECTION INPUT ;
    USE SIGNAL ;
    SHAPE ABUTMENT ;
    PORT
      LAYER M4 ;
      RECT 0.000 128.976 0.024 129.000 ;
    END
  END wd_in[35]
  PIN wd_in[36]
    DIRECTION INPUT ;
    USE SIGNAL ;
    SHAPE ABUTMENT ;
    PORT
      LAYER M4 ;
      RECT 0.000 129.744 0.024 129.768 ;
    END
  END wd_in[36]
  PIN wd_in[37]
    DIRECTION INPUT ;
    USE SIGNAL ;
    SHAPE ABUTMENT ;
    PORT
      LAYER M4 ;
      RECT 0.000 130.512 0.024 130.536 ;
    END
  END wd_in[37]
  PIN wd_in[38]
    DIRECTION INPUT ;
    USE SIGNAL ;
    SHAPE ABUTMENT ;
    PORT
      LAYER M4 ;
      RECT 0.000 131.280 0.024 131.304 ;
    END
  END wd_in[38]
  PIN wd_in[39]
    DIRECTION INPUT ;
    USE SIGNAL ;
    SHAPE ABUTMENT ;
    PORT
      LAYER M4 ;
      RECT 0.000 132.048 0.024 132.072 ;
    END
  END wd_in[39]
  PIN wd_in[40]
    DIRECTION INPUT ;
    USE SIGNAL ;
    SHAPE ABUTMENT ;
    PORT
      LAYER M4 ;
      RECT 0.000 132.816 0.024 132.840 ;
    END
  END wd_in[40]
  PIN wd_in[41]
    DIRECTION INPUT ;
    USE SIGNAL ;
    SHAPE ABUTMENT ;
    PORT
      LAYER M4 ;
      RECT 0.000 133.584 0.024 133.608 ;
    END
  END wd_in[41]
  PIN wd_in[42]
    DIRECTION INPUT ;
    USE SIGNAL ;
    SHAPE ABUTMENT ;
    PORT
      LAYER M4 ;
      RECT 0.000 134.352 0.024 134.376 ;
    END
  END wd_in[42]
  PIN wd_in[43]
    DIRECTION INPUT ;
    USE SIGNAL ;
    SHAPE ABUTMENT ;
    PORT
      LAYER M4 ;
      RECT 0.000 135.120 0.024 135.144 ;
    END
  END wd_in[43]
  PIN wd_in[44]
    DIRECTION INPUT ;
    USE SIGNAL ;
    SHAPE ABUTMENT ;
    PORT
      LAYER M4 ;
      RECT 0.000 135.888 0.024 135.912 ;
    END
  END wd_in[44]
  PIN wd_in[45]
    DIRECTION INPUT ;
    USE SIGNAL ;
    SHAPE ABUTMENT ;
    PORT
      LAYER M4 ;
      RECT 0.000 136.656 0.024 136.680 ;
    END
  END wd_in[45]
  PIN wd_in[46]
    DIRECTION INPUT ;
    USE SIGNAL ;
    SHAPE ABUTMENT ;
    PORT
      LAYER M4 ;
      RECT 0.000 137.424 0.024 137.448 ;
    END
  END wd_in[46]
  PIN wd_in[47]
    DIRECTION INPUT ;
    USE SIGNAL ;
    SHAPE ABUTMENT ;
    PORT
      LAYER M4 ;
      RECT 0.000 138.192 0.024 138.216 ;
    END
  END wd_in[47]
  PIN wd_in[48]
    DIRECTION INPUT ;
    USE SIGNAL ;
    SHAPE ABUTMENT ;
    PORT
      LAYER M4 ;
      RECT 0.000 138.960 0.024 138.984 ;
    END
  END wd_in[48]
  PIN wd_in[49]
    DIRECTION INPUT ;
    USE SIGNAL ;
    SHAPE ABUTMENT ;
    PORT
      LAYER M4 ;
      RECT 0.000 139.728 0.024 139.752 ;
    END
  END wd_in[49]
  PIN wd_in[50]
    DIRECTION INPUT ;
    USE SIGNAL ;
    SHAPE ABUTMENT ;
    PORT
      LAYER M4 ;
      RECT 0.000 140.496 0.024 140.520 ;
    END
  END wd_in[50]
  PIN wd_in[51]
    DIRECTION INPUT ;
    USE SIGNAL ;
    SHAPE ABUTMENT ;
    PORT
      LAYER M4 ;
      RECT 0.000 141.264 0.024 141.288 ;
    END
  END wd_in[51]
  PIN wd_in[52]
    DIRECTION INPUT ;
    USE SIGNAL ;
    SHAPE ABUTMENT ;
    PORT
      LAYER M4 ;
      RECT 0.000 142.032 0.024 142.056 ;
    END
  END wd_in[52]
  PIN wd_in[53]
    DIRECTION INPUT ;
    USE SIGNAL ;
    SHAPE ABUTMENT ;
    PORT
      LAYER M4 ;
      RECT 0.000 142.800 0.024 142.824 ;
    END
  END wd_in[53]
  PIN wd_in[54]
    DIRECTION INPUT ;
    USE SIGNAL ;
    SHAPE ABUTMENT ;
    PORT
      LAYER M4 ;
      RECT 0.000 143.568 0.024 143.592 ;
    END
  END wd_in[54]
  PIN wd_in[55]
    DIRECTION INPUT ;
    USE SIGNAL ;
    SHAPE ABUTMENT ;
    PORT
      LAYER M4 ;
      RECT 0.000 144.336 0.024 144.360 ;
    END
  END wd_in[55]
  PIN wd_in[56]
    DIRECTION INPUT ;
    USE SIGNAL ;
    SHAPE ABUTMENT ;
    PORT
      LAYER M4 ;
      RECT 0.000 145.104 0.024 145.128 ;
    END
  END wd_in[56]
  PIN wd_in[57]
    DIRECTION INPUT ;
    USE SIGNAL ;
    SHAPE ABUTMENT ;
    PORT
      LAYER M4 ;
      RECT 0.000 145.872 0.024 145.896 ;
    END
  END wd_in[57]
  PIN wd_in[58]
    DIRECTION INPUT ;
    USE SIGNAL ;
    SHAPE ABUTMENT ;
    PORT
      LAYER M4 ;
      RECT 0.000 146.640 0.024 146.664 ;
    END
  END wd_in[58]
  PIN wd_in[59]
    DIRECTION INPUT ;
    USE SIGNAL ;
    SHAPE ABUTMENT ;
    PORT
      LAYER M4 ;
      RECT 0.000 147.408 0.024 147.432 ;
    END
  END wd_in[59]
  PIN wd_in[60]
    DIRECTION INPUT ;
    USE SIGNAL ;
    SHAPE ABUTMENT ;
    PORT
      LAYER M4 ;
      RECT 0.000 148.176 0.024 148.200 ;
    END
  END wd_in[60]
  PIN wd_in[61]
    DIRECTION INPUT ;
    USE SIGNAL ;
    SHAPE ABUTMENT ;
    PORT
      LAYER M4 ;
      RECT 0.000 148.944 0.024 148.968 ;
    END
  END wd_in[61]
  PIN wd_in[62]
    DIRECTION INPUT ;
    USE SIGNAL ;
    SHAPE ABUTMENT ;
    PORT
      LAYER M4 ;
      RECT 0.000 149.712 0.024 149.736 ;
    END
  END wd_in[62]
  PIN wd_in[63]
    DIRECTION INPUT ;
    USE SIGNAL ;
    SHAPE ABUTMENT ;
    PORT
      LAYER M4 ;
      RECT 0.000 150.480 0.024 150.504 ;
    END
  END wd_in[63]
  PIN addr_in[0]
    DIRECTION INPUT ;
    USE SIGNAL ;
    SHAPE ABUTMENT ;
    PORT
      LAYER M4 ;
      RECT 0.000 153.120 0.024 153.144 ;
    END
  END addr_in[0]
  PIN addr_in[1]
    DIRECTION INPUT ;
    USE SIGNAL ;
    SHAPE ABUTMENT ;
    PORT
      LAYER M4 ;
      RECT 0.000 153.888 0.024 153.912 ;
    END
  END addr_in[1]
  PIN addr_in[2]
    DIRECTION INPUT ;
    USE SIGNAL ;
    SHAPE ABUTMENT ;
    PORT
      LAYER M4 ;
      RECT 0.000 154.656 0.024 154.680 ;
    END
  END addr_in[2]
  PIN addr_in[3]
    DIRECTION INPUT ;
    USE SIGNAL ;
    SHAPE ABUTMENT ;
    PORT
      LAYER M4 ;
      RECT 0.000 155.424 0.024 155.448 ;
    END
  END addr_in[3]
  PIN addr_in[4]
    DIRECTION INPUT ;
    USE SIGNAL ;
    SHAPE ABUTMENT ;
    PORT
      LAYER M4 ;
      RECT 0.000 156.192 0.024 156.216 ;
    END
  END addr_in[4]
  PIN addr_in[5]
    DIRECTION INPUT ;
    USE SIGNAL ;
    SHAPE ABUTMENT ;
    PORT
      LAYER M4 ;
      RECT 0.000 156.960 0.024 156.984 ;
    END
  END addr_in[5]
  PIN addr_in[6]
    DIRECTION INPUT ;
    USE SIGNAL ;
    SHAPE ABUTMENT ;
    PORT
      LAYER M4 ;
      RECT 0.000 157.728 0.024 157.752 ;
    END
  END addr_in[6]
  PIN addr_in[7]
    DIRECTION INPUT ;
    USE SIGNAL ;
    SHAPE ABUTMENT ;
    PORT
      LAYER M4 ;
      RECT 0.000 158.496 0.024 158.520 ;
    END
  END addr_in[7]
  PIN addr_in[8]
    DIRECTION INPUT ;
    USE SIGNAL ;
    SHAPE ABUTMENT ;
    PORT
      LAYER M4 ;
      RECT 0.000 159.264 0.024 159.288 ;
    END
  END addr_in[8]
  PIN addr_in[9]
    DIRECTION INPUT ;
    USE SIGNAL ;
    SHAPE ABUTMENT ;
    PORT
      LAYER M4 ;
      RECT 0.000 160.032 0.024 160.056 ;
    END
  END addr_in[9]
  PIN addr_in[10]
    DIRECTION INPUT ;
    USE SIGNAL ;
    SHAPE ABUTMENT ;
    PORT
      LAYER M4 ;
      RECT 0.000 160.800 0.024 160.824 ;
    END
  END addr_in[10]
  PIN addr_in[11]
    DIRECTION INPUT ;
    USE SIGNAL ;
    SHAPE ABUTMENT ;
    PORT
      LAYER M4 ;
      RECT 0.000 161.568 0.024 161.592 ;
    END
  END addr_in[11]
  PIN we_in
    DIRECTION INPUT ;
    USE SIGNAL ;
    SHAPE ABUTMENT ;
    PORT
      LAYER M4 ;
      RECT 0.000 164.208 0.024 164.232 ;
    END
  END we_in
  PIN ce_in
    DIRECTION INPUT ;
    USE SIGNAL ;
    SHAPE ABUTMENT ;
    PORT
      LAYER M4 ;
      RECT 0.000 164.976 0.024 165.000 ;
    END
  END ce_in
  PIN clk
    DIRECTION INPUT ;
    USE SIGNAL ;
    SHAPE ABUTMENT ;
    PORT
      LAYER M4 ;
      RECT 0.000 165.744 0.024 165.768 ;
    END
  END clk
  PIN VSS
    DIRECTION INOUT ;
    USE GROUND ;
    PORT
      LAYER M4 ;
      RECT 0.048 0.000 66.452 0.096 ;
      RECT 0.048 0.768 66.452 0.864 ;
      RECT 0.048 1.536 66.452 1.632 ;
      RECT 0.048 2.304 66.452 2.400 ;
      RECT 0.048 3.072 66.452 3.168 ;
      RECT 0.048 3.840 66.452 3.936 ;
      RECT 0.048 4.608 66.452 4.704 ;
      RECT 0.048 5.376 66.452 5.472 ;
      RECT 0.048 6.144 66.452 6.240 ;
      RECT 0.048 6.912 66.452 7.008 ;
      RECT 0.048 7.680 66.452 7.776 ;
      RECT 0.048 8.448 66.452 8.544 ;
      RECT 0.048 9.216 66.452 9.312 ;
      RECT 0.048 9.984 66.452 10.080 ;
      RECT 0.048 10.752 66.452 10.848 ;
      RECT 0.048 11.520 66.452 11.616 ;
      RECT 0.048 12.288 66.452 12.384 ;
      RECT 0.048 13.056 66.452 13.152 ;
      RECT 0.048 13.824 66.452 13.920 ;
      RECT 0.048 14.592 66.452 14.688 ;
      RECT 0.048 15.360 66.452 15.456 ;
      RECT 0.048 16.128 66.452 16.224 ;
      RECT 0.048 16.896 66.452 16.992 ;
      RECT 0.048 17.664 66.452 17.760 ;
      RECT 0.048 18.432 66.452 18.528 ;
      RECT 0.048 19.200 66.452 19.296 ;
      RECT 0.048 19.968 66.452 20.064 ;
      RECT 0.048 20.736 66.452 20.832 ;
      RECT 0.048 21.504 66.452 21.600 ;
      RECT 0.048 22.272 66.452 22.368 ;
      RECT 0.048 23.040 66.452 23.136 ;
      RECT 0.048 23.808 66.452 23.904 ;
      RECT 0.048 24.576 66.452 24.672 ;
      RECT 0.048 25.344 66.452 25.440 ;
      RECT 0.048 26.112 66.452 26.208 ;
      RECT 0.048 26.880 66.452 26.976 ;
      RECT 0.048 27.648 66.452 27.744 ;
      RECT 0.048 28.416 66.452 28.512 ;
      RECT 0.048 29.184 66.452 29.280 ;
      RECT 0.048 29.952 66.452 30.048 ;
      RECT 0.048 30.720 66.452 30.816 ;
      RECT 0.048 31.488 66.452 31.584 ;
      RECT 0.048 32.256 66.452 32.352 ;
      RECT 0.048 33.024 66.452 33.120 ;
      RECT 0.048 33.792 66.452 33.888 ;
      RECT 0.048 34.560 66.452 34.656 ;
      RECT 0.048 35.328 66.452 35.424 ;
      RECT 0.048 36.096 66.452 36.192 ;
      RECT 0.048 36.864 66.452 36.960 ;
      RECT 0.048 37.632 66.452 37.728 ;
      RECT 0.048 38.400 66.452 38.496 ;
      RECT 0.048 39.168 66.452 39.264 ;
      RECT 0.048 39.936 66.452 40.032 ;
      RECT 0.048 40.704 66.452 40.800 ;
      RECT 0.048 41.472 66.452 41.568 ;
      RECT 0.048 42.240 66.452 42.336 ;
      RECT 0.048 43.008 66.452 43.104 ;
      RECT 0.048 43.776 66.452 43.872 ;
      RECT 0.048 44.544 66.452 44.640 ;
      RECT 0.048 45.312 66.452 45.408 ;
      RECT 0.048 46.080 66.452 46.176 ;
      RECT 0.048 46.848 66.452 46.944 ;
      RECT 0.048 47.616 66.452 47.712 ;
      RECT 0.048 48.384 66.452 48.480 ;
      RECT 0.048 49.152 66.452 49.248 ;
      RECT 0.048 49.920 66.452 50.016 ;
      RECT 0.048 50.688 66.452 50.784 ;
      RECT 0.048 51.456 66.452 51.552 ;
      RECT 0.048 52.224 66.452 52.320 ;
      RECT 0.048 52.992 66.452 53.088 ;
      RECT 0.048 53.760 66.452 53.856 ;
      RECT 0.048 54.528 66.452 54.624 ;
      RECT 0.048 55.296 66.452 55.392 ;
      RECT 0.048 56.064 66.452 56.160 ;
      RECT 0.048 56.832 66.452 56.928 ;
      RECT 0.048 57.600 66.452 57.696 ;
      RECT 0.048 58.368 66.452 58.464 ;
      RECT 0.048 59.136 66.452 59.232 ;
      RECT 0.048 59.904 66.452 60.000 ;
      RECT 0.048 60.672 66.452 60.768 ;
      RECT 0.048 61.440 66.452 61.536 ;
      RECT 0.048 62.208 66.452 62.304 ;
      RECT 0.048 62.976 66.452 63.072 ;
      RECT 0.048 63.744 66.452 63.840 ;
      RECT 0.048 64.512 66.452 64.608 ;
      RECT 0.048 65.280 66.452 65.376 ;
      RECT 0.048 66.048 66.452 66.144 ;
      RECT 0.048 66.816 66.452 66.912 ;
      RECT 0.048 67.584 66.452 67.680 ;
      RECT 0.048 68.352 66.452 68.448 ;
      RECT 0.048 69.120 66.452 69.216 ;
      RECT 0.048 69.888 66.452 69.984 ;
      RECT 0.048 70.656 66.452 70.752 ;
      RECT 0.048 71.424 66.452 71.520 ;
      RECT 0.048 72.192 66.452 72.288 ;
      RECT 0.048 72.960 66.452 73.056 ;
      RECT 0.048 73.728 66.452 73.824 ;
      RECT 0.048 74.496 66.452 74.592 ;
      RECT 0.048 75.264 66.452 75.360 ;
      RECT 0.048 76.032 66.452 76.128 ;
      RECT 0.048 76.800 66.452 76.896 ;
      RECT 0.048 77.568 66.452 77.664 ;
      RECT 0.048 78.336 66.452 78.432 ;
      RECT 0.048 79.104 66.452 79.200 ;
      RECT 0.048 79.872 66.452 79.968 ;
      RECT 0.048 80.640 66.452 80.736 ;
      RECT 0.048 81.408 66.452 81.504 ;
      RECT 0.048 82.176 66.452 82.272 ;
      RECT 0.048 82.944 66.452 83.040 ;
      RECT 0.048 83.712 66.452 83.808 ;
      RECT 0.048 84.480 66.452 84.576 ;
      RECT 0.048 85.248 66.452 85.344 ;
      RECT 0.048 86.016 66.452 86.112 ;
      RECT 0.048 86.784 66.452 86.880 ;
      RECT 0.048 87.552 66.452 87.648 ;
      RECT 0.048 88.320 66.452 88.416 ;
      RECT 0.048 89.088 66.452 89.184 ;
      RECT 0.048 89.856 66.452 89.952 ;
      RECT 0.048 90.624 66.452 90.720 ;
      RECT 0.048 91.392 66.452 91.488 ;
      RECT 0.048 92.160 66.452 92.256 ;
      RECT 0.048 92.928 66.452 93.024 ;
      RECT 0.048 93.696 66.452 93.792 ;
      RECT 0.048 94.464 66.452 94.560 ;
      RECT 0.048 95.232 66.452 95.328 ;
      RECT 0.048 96.000 66.452 96.096 ;
      RECT 0.048 96.768 66.452 96.864 ;
      RECT 0.048 97.536 66.452 97.632 ;
      RECT 0.048 98.304 66.452 98.400 ;
      RECT 0.048 99.072 66.452 99.168 ;
      RECT 0.048 99.840 66.452 99.936 ;
      RECT 0.048 100.608 66.452 100.704 ;
      RECT 0.048 101.376 66.452 101.472 ;
      RECT 0.048 102.144 66.452 102.240 ;
      RECT 0.048 102.912 66.452 103.008 ;
      RECT 0.048 103.680 66.452 103.776 ;
      RECT 0.048 104.448 66.452 104.544 ;
      RECT 0.048 105.216 66.452 105.312 ;
      RECT 0.048 105.984 66.452 106.080 ;
      RECT 0.048 106.752 66.452 106.848 ;
      RECT 0.048 107.520 66.452 107.616 ;
      RECT 0.048 108.288 66.452 108.384 ;
      RECT 0.048 109.056 66.452 109.152 ;
      RECT 0.048 109.824 66.452 109.920 ;
      RECT 0.048 110.592 66.452 110.688 ;
      RECT 0.048 111.360 66.452 111.456 ;
      RECT 0.048 112.128 66.452 112.224 ;
      RECT 0.048 112.896 66.452 112.992 ;
      RECT 0.048 113.664 66.452 113.760 ;
      RECT 0.048 114.432 66.452 114.528 ;
      RECT 0.048 115.200 66.452 115.296 ;
      RECT 0.048 115.968 66.452 116.064 ;
      RECT 0.048 116.736 66.452 116.832 ;
      RECT 0.048 117.504 66.452 117.600 ;
      RECT 0.048 118.272 66.452 118.368 ;
      RECT 0.048 119.040 66.452 119.136 ;
      RECT 0.048 119.808 66.452 119.904 ;
      RECT 0.048 120.576 66.452 120.672 ;
      RECT 0.048 121.344 66.452 121.440 ;
      RECT 0.048 122.112 66.452 122.208 ;
      RECT 0.048 122.880 66.452 122.976 ;
      RECT 0.048 123.648 66.452 123.744 ;
      RECT 0.048 124.416 66.452 124.512 ;
      RECT 0.048 125.184 66.452 125.280 ;
      RECT 0.048 125.952 66.452 126.048 ;
      RECT 0.048 126.720 66.452 126.816 ;
      RECT 0.048 127.488 66.452 127.584 ;
      RECT 0.048 128.256 66.452 128.352 ;
      RECT 0.048 129.024 66.452 129.120 ;
      RECT 0.048 129.792 66.452 129.888 ;
      RECT 0.048 130.560 66.452 130.656 ;
      RECT 0.048 131.328 66.452 131.424 ;
      RECT 0.048 132.096 66.452 132.192 ;
      RECT 0.048 132.864 66.452 132.960 ;
      RECT 0.048 133.632 66.452 133.728 ;
      RECT 0.048 134.400 66.452 134.496 ;
      RECT 0.048 135.168 66.452 135.264 ;
      RECT 0.048 135.936 66.452 136.032 ;
      RECT 0.048 136.704 66.452 136.800 ;
      RECT 0.048 137.472 66.452 137.568 ;
      RECT 0.048 138.240 66.452 138.336 ;
      RECT 0.048 139.008 66.452 139.104 ;
      RECT 0.048 139.776 66.452 139.872 ;
      RECT 0.048 140.544 66.452 140.640 ;
      RECT 0.048 141.312 66.452 141.408 ;
      RECT 0.048 142.080 66.452 142.176 ;
      RECT 0.048 142.848 66.452 142.944 ;
      RECT 0.048 143.616 66.452 143.712 ;
      RECT 0.048 144.384 66.452 144.480 ;
      RECT 0.048 145.152 66.452 145.248 ;
      RECT 0.048 145.920 66.452 146.016 ;
      RECT 0.048 146.688 66.452 146.784 ;
      RECT 0.048 147.456 66.452 147.552 ;
      RECT 0.048 148.224 66.452 148.320 ;
      RECT 0.048 148.992 66.452 149.088 ;
      RECT 0.048 149.760 66.452 149.856 ;
      RECT 0.048 150.528 66.452 150.624 ;
      RECT 0.048 151.296 66.452 151.392 ;
      RECT 0.048 152.064 66.452 152.160 ;
      RECT 0.048 152.832 66.452 152.928 ;
      RECT 0.048 153.600 66.452 153.696 ;
      RECT 0.048 154.368 66.452 154.464 ;
      RECT 0.048 155.136 66.452 155.232 ;
      RECT 0.048 155.904 66.452 156.000 ;
      RECT 0.048 156.672 66.452 156.768 ;
      RECT 0.048 157.440 66.452 157.536 ;
      RECT 0.048 158.208 66.452 158.304 ;
      RECT 0.048 158.976 66.452 159.072 ;
      RECT 0.048 159.744 66.452 159.840 ;
      RECT 0.048 160.512 66.452 160.608 ;
      RECT 0.048 161.280 66.452 161.376 ;
      RECT 0.048 162.048 66.452 162.144 ;
      RECT 0.048 162.816 66.452 162.912 ;
      RECT 0.048 163.584 66.452 163.680 ;
      RECT 0.048 164.352 66.452 164.448 ;
      RECT 0.048 165.120 66.452 165.216 ;
      RECT 0.048 165.888 66.452 165.984 ;
    END
  END VSS
  PIN VDD
    DIRECTION INOUT ;
    USE POWER ;
    PORT
      LAYER M4 ;
      RECT 0.048 0.384 66.452 0.480 ;
      RECT 0.048 1.152 66.452 1.248 ;
      RECT 0.048 1.920 66.452 2.016 ;
      RECT 0.048 2.688 66.452 2.784 ;
      RECT 0.048 3.456 66.452 3.552 ;
      RECT 0.048 4.224 66.452 4.320 ;
      RECT 0.048 4.992 66.452 5.088 ;
      RECT 0.048 5.760 66.452 5.856 ;
      RECT 0.048 6.528 66.452 6.624 ;
      RECT 0.048 7.296 66.452 7.392 ;
      RECT 0.048 8.064 66.452 8.160 ;
      RECT 0.048 8.832 66.452 8.928 ;
      RECT 0.048 9.600 66.452 9.696 ;
      RECT 0.048 10.368 66.452 10.464 ;
      RECT 0.048 11.136 66.452 11.232 ;
      RECT 0.048 11.904 66.452 12.000 ;
      RECT 0.048 12.672 66.452 12.768 ;
      RECT 0.048 13.440 66.452 13.536 ;
      RECT 0.048 14.208 66.452 14.304 ;
      RECT 0.048 14.976 66.452 15.072 ;
      RECT 0.048 15.744 66.452 15.840 ;
      RECT 0.048 16.512 66.452 16.608 ;
      RECT 0.048 17.280 66.452 17.376 ;
      RECT 0.048 18.048 66.452 18.144 ;
      RECT 0.048 18.816 66.452 18.912 ;
      RECT 0.048 19.584 66.452 19.680 ;
      RECT 0.048 20.352 66.452 20.448 ;
      RECT 0.048 21.120 66.452 21.216 ;
      RECT 0.048 21.888 66.452 21.984 ;
      RECT 0.048 22.656 66.452 22.752 ;
      RECT 0.048 23.424 66.452 23.520 ;
      RECT 0.048 24.192 66.452 24.288 ;
      RECT 0.048 24.960 66.452 25.056 ;
      RECT 0.048 25.728 66.452 25.824 ;
      RECT 0.048 26.496 66.452 26.592 ;
      RECT 0.048 27.264 66.452 27.360 ;
      RECT 0.048 28.032 66.452 28.128 ;
      RECT 0.048 28.800 66.452 28.896 ;
      RECT 0.048 29.568 66.452 29.664 ;
      RECT 0.048 30.336 66.452 30.432 ;
      RECT 0.048 31.104 66.452 31.200 ;
      RECT 0.048 31.872 66.452 31.968 ;
      RECT 0.048 32.640 66.452 32.736 ;
      RECT 0.048 33.408 66.452 33.504 ;
      RECT 0.048 34.176 66.452 34.272 ;
      RECT 0.048 34.944 66.452 35.040 ;
      RECT 0.048 35.712 66.452 35.808 ;
      RECT 0.048 36.480 66.452 36.576 ;
      RECT 0.048 37.248 66.452 37.344 ;
      RECT 0.048 38.016 66.452 38.112 ;
      RECT 0.048 38.784 66.452 38.880 ;
      RECT 0.048 39.552 66.452 39.648 ;
      RECT 0.048 40.320 66.452 40.416 ;
      RECT 0.048 41.088 66.452 41.184 ;
      RECT 0.048 41.856 66.452 41.952 ;
      RECT 0.048 42.624 66.452 42.720 ;
      RECT 0.048 43.392 66.452 43.488 ;
      RECT 0.048 44.160 66.452 44.256 ;
      RECT 0.048 44.928 66.452 45.024 ;
      RECT 0.048 45.696 66.452 45.792 ;
      RECT 0.048 46.464 66.452 46.560 ;
      RECT 0.048 47.232 66.452 47.328 ;
      RECT 0.048 48.000 66.452 48.096 ;
      RECT 0.048 48.768 66.452 48.864 ;
      RECT 0.048 49.536 66.452 49.632 ;
      RECT 0.048 50.304 66.452 50.400 ;
      RECT 0.048 51.072 66.452 51.168 ;
      RECT 0.048 51.840 66.452 51.936 ;
      RECT 0.048 52.608 66.452 52.704 ;
      RECT 0.048 53.376 66.452 53.472 ;
      RECT 0.048 54.144 66.452 54.240 ;
      RECT 0.048 54.912 66.452 55.008 ;
      RECT 0.048 55.680 66.452 55.776 ;
      RECT 0.048 56.448 66.452 56.544 ;
      RECT 0.048 57.216 66.452 57.312 ;
      RECT 0.048 57.984 66.452 58.080 ;
      RECT 0.048 58.752 66.452 58.848 ;
      RECT 0.048 59.520 66.452 59.616 ;
      RECT 0.048 60.288 66.452 60.384 ;
      RECT 0.048 61.056 66.452 61.152 ;
      RECT 0.048 61.824 66.452 61.920 ;
      RECT 0.048 62.592 66.452 62.688 ;
      RECT 0.048 63.360 66.452 63.456 ;
      RECT 0.048 64.128 66.452 64.224 ;
      RECT 0.048 64.896 66.452 64.992 ;
      RECT 0.048 65.664 66.452 65.760 ;
      RECT 0.048 66.432 66.452 66.528 ;
      RECT 0.048 67.200 66.452 67.296 ;
      RECT 0.048 67.968 66.452 68.064 ;
      RECT 0.048 68.736 66.452 68.832 ;
      RECT 0.048 69.504 66.452 69.600 ;
      RECT 0.048 70.272 66.452 70.368 ;
      RECT 0.048 71.040 66.452 71.136 ;
      RECT 0.048 71.808 66.452 71.904 ;
      RECT 0.048 72.576 66.452 72.672 ;
      RECT 0.048 73.344 66.452 73.440 ;
      RECT 0.048 74.112 66.452 74.208 ;
      RECT 0.048 74.880 66.452 74.976 ;
      RECT 0.048 75.648 66.452 75.744 ;
      RECT 0.048 76.416 66.452 76.512 ;
      RECT 0.048 77.184 66.452 77.280 ;
      RECT 0.048 77.952 66.452 78.048 ;
      RECT 0.048 78.720 66.452 78.816 ;
      RECT 0.048 79.488 66.452 79.584 ;
      RECT 0.048 80.256 66.452 80.352 ;
      RECT 0.048 81.024 66.452 81.120 ;
      RECT 0.048 81.792 66.452 81.888 ;
      RECT 0.048 82.560 66.452 82.656 ;
      RECT 0.048 83.328 66.452 83.424 ;
      RECT 0.048 84.096 66.452 84.192 ;
      RECT 0.048 84.864 66.452 84.960 ;
      RECT 0.048 85.632 66.452 85.728 ;
      RECT 0.048 86.400 66.452 86.496 ;
      RECT 0.048 87.168 66.452 87.264 ;
      RECT 0.048 87.936 66.452 88.032 ;
      RECT 0.048 88.704 66.452 88.800 ;
      RECT 0.048 89.472 66.452 89.568 ;
      RECT 0.048 90.240 66.452 90.336 ;
      RECT 0.048 91.008 66.452 91.104 ;
      RECT 0.048 91.776 66.452 91.872 ;
      RECT 0.048 92.544 66.452 92.640 ;
      RECT 0.048 93.312 66.452 93.408 ;
      RECT 0.048 94.080 66.452 94.176 ;
      RECT 0.048 94.848 66.452 94.944 ;
      RECT 0.048 95.616 66.452 95.712 ;
      RECT 0.048 96.384 66.452 96.480 ;
      RECT 0.048 97.152 66.452 97.248 ;
      RECT 0.048 97.920 66.452 98.016 ;
      RECT 0.048 98.688 66.452 98.784 ;
      RECT 0.048 99.456 66.452 99.552 ;
      RECT 0.048 100.224 66.452 100.320 ;
      RECT 0.048 100.992 66.452 101.088 ;
      RECT 0.048 101.760 66.452 101.856 ;
      RECT 0.048 102.528 66.452 102.624 ;
      RECT 0.048 103.296 66.452 103.392 ;
      RECT 0.048 104.064 66.452 104.160 ;
      RECT 0.048 104.832 66.452 104.928 ;
      RECT 0.048 105.600 66.452 105.696 ;
      RECT 0.048 106.368 66.452 106.464 ;
      RECT 0.048 107.136 66.452 107.232 ;
      RECT 0.048 107.904 66.452 108.000 ;
      RECT 0.048 108.672 66.452 108.768 ;
      RECT 0.048 109.440 66.452 109.536 ;
      RECT 0.048 110.208 66.452 110.304 ;
      RECT 0.048 110.976 66.452 111.072 ;
      RECT 0.048 111.744 66.452 111.840 ;
      RECT 0.048 112.512 66.452 112.608 ;
      RECT 0.048 113.280 66.452 113.376 ;
      RECT 0.048 114.048 66.452 114.144 ;
      RECT 0.048 114.816 66.452 114.912 ;
      RECT 0.048 115.584 66.452 115.680 ;
      RECT 0.048 116.352 66.452 116.448 ;
      RECT 0.048 117.120 66.452 117.216 ;
      RECT 0.048 117.888 66.452 117.984 ;
      RECT 0.048 118.656 66.452 118.752 ;
      RECT 0.048 119.424 66.452 119.520 ;
      RECT 0.048 120.192 66.452 120.288 ;
      RECT 0.048 120.960 66.452 121.056 ;
      RECT 0.048 121.728 66.452 121.824 ;
      RECT 0.048 122.496 66.452 122.592 ;
      RECT 0.048 123.264 66.452 123.360 ;
      RECT 0.048 124.032 66.452 124.128 ;
      RECT 0.048 124.800 66.452 124.896 ;
      RECT 0.048 125.568 66.452 125.664 ;
      RECT 0.048 126.336 66.452 126.432 ;
      RECT 0.048 127.104 66.452 127.200 ;
      RECT 0.048 127.872 66.452 127.968 ;
      RECT 0.048 128.640 66.452 128.736 ;
      RECT 0.048 129.408 66.452 129.504 ;
      RECT 0.048 130.176 66.452 130.272 ;
      RECT 0.048 130.944 66.452 131.040 ;
      RECT 0.048 131.712 66.452 131.808 ;
      RECT 0.048 132.480 66.452 132.576 ;
      RECT 0.048 133.248 66.452 133.344 ;
      RECT 0.048 134.016 66.452 134.112 ;
      RECT 0.048 134.784 66.452 134.880 ;
      RECT 0.048 135.552 66.452 135.648 ;
      RECT 0.048 136.320 66.452 136.416 ;
      RECT 0.048 137.088 66.452 137.184 ;
      RECT 0.048 137.856 66.452 137.952 ;
      RECT 0.048 138.624 66.452 138.720 ;
      RECT 0.048 139.392 66.452 139.488 ;
      RECT 0.048 140.160 66.452 140.256 ;
      RECT 0.048 140.928 66.452 141.024 ;
      RECT 0.048 141.696 66.452 141.792 ;
      RECT 0.048 142.464 66.452 142.560 ;
      RECT 0.048 143.232 66.452 143.328 ;
      RECT 0.048 144.000 66.452 144.096 ;
      RECT 0.048 144.768 66.452 144.864 ;
      RECT 0.048 145.536 66.452 145.632 ;
      RECT 0.048 146.304 66.452 146.400 ;
      RECT 0.048 147.072 66.452 147.168 ;
      RECT 0.048 147.840 66.452 147.936 ;
      RECT 0.048 148.608 66.452 148.704 ;
      RECT 0.048 149.376 66.452 149.472 ;
      RECT 0.048 150.144 66.452 150.240 ;
      RECT 0.048 150.912 66.452 151.008 ;
      RECT 0.048 151.680 66.452 151.776 ;
      RECT 0.048 152.448 66.452 152.544 ;
      RECT 0.048 153.216 66.452 153.312 ;
      RECT 0.048 153.984 66.452 154.080 ;
      RECT 0.048 154.752 66.452 154.848 ;
      RECT 0.048 155.520 66.452 155.616 ;
      RECT 0.048 156.288 66.452 156.384 ;
      RECT 0.048 157.056 66.452 157.152 ;
      RECT 0.048 157.824 66.452 157.920 ;
      RECT 0.048 158.592 66.452 158.688 ;
      RECT 0.048 159.360 66.452 159.456 ;
      RECT 0.048 160.128 66.452 160.224 ;
      RECT 0.048 160.896 66.452 160.992 ;
      RECT 0.048 161.664 66.452 161.760 ;
      RECT 0.048 162.432 66.452 162.528 ;
      RECT 0.048 163.200 66.452 163.296 ;
      RECT 0.048 163.968 66.452 164.064 ;
      RECT 0.048 164.736 66.452 164.832 ;
      RECT 0.048 165.504 66.452 165.600 ;
      RECT 0.048 166.272 66.452 166.368 ;
    END
  END VDD
  OBS
    LAYER M1 ;
    RECT 0 0 66.500 166.600 ;
    LAYER M2 ;
    RECT 0 0 66.500 166.600 ;
    LAYER M3 ;
    RECT 0 0 66.500 166.600 ;
    LAYER M4 ;
    RECT 0 0 66.500 166.600 ;
  END
END fakeram7_sp_4096x64

END LIBRARY
